VERSION 5.7 ;
  NOWIREEXTENSIONATPIN ON ;
  DIVIDERCHAR "/" ;
  BUSBITCHARS "[]" ;
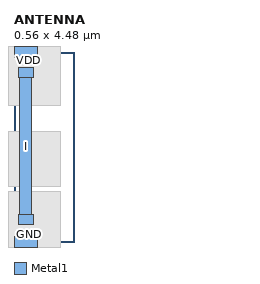
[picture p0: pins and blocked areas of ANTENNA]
MACRO ANTENNA
  CLASS core ;
  FOREIGN ANTENNA ;
  ORIGIN 0.000 0.000 ;
  SIZE 0.560 BY 4.480 ;
  SYMMETRY X Y ;
  SITE site056um ;
  PIN GND
    DIRECTION INOUT ;
    USE GROUND ;
    PORT
      LAYER Metal1 ;
        RECT 0.000 -0.140 0.560 0.140 ;
    END
  END GND
  PIN VDD
    DIRECTION INOUT ;
    USE POWER ;
    PORT
      LAYER Metal1 ;
        RECT 0.000 4.340 0.560 4.620 ;
    END
  END VDD
  PIN I
    DIRECTION INPUT ;
    USE SIGNAL ;
    ANTENNADIFFAREA 0.412500 ;
    PORT
      LAYER Metal1 ;
        RECT 0.110 3.875 0.450 4.105 ;
        RECT 0.140 0.645 0.420 3.875 ;
        RECT 0.110 0.415 0.450 0.645 ;
    END
  END I
  OBS
      LAYER Nwell ;
        RECT -0.530 3.210 1.090 4.900 ;
        RECT -0.530 1.310 1.090 2.610 ;
      LAYER Pwell ;
        RECT -0.530 -0.140 1.090 1.185 ;
  END
END ANTENNA
END LIBRARY

